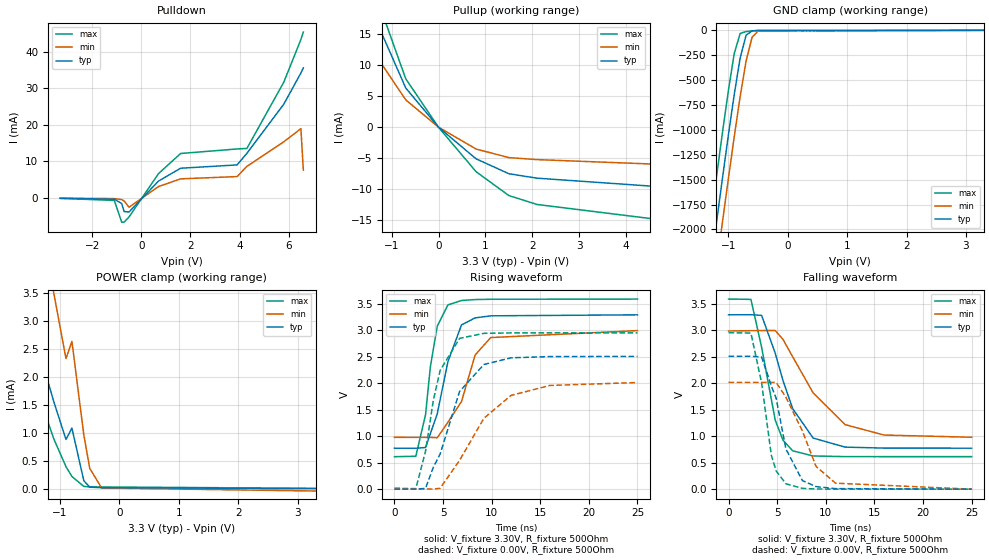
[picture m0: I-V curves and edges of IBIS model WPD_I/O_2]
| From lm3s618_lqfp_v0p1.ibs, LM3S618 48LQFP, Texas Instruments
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[Model]   WPD_I/O_2
Model_type   I/O
Vinl = 1.26
Vinh = 2.04
Vmeas = 1.65
| variable   typ   min   max
C_comp   9.739pF   9.739pF   9.739pF
[Model Spec]
Vinh+   1.91   1.78   2.04
Vinh-   1.90   1.76   2.03
Vinl+   1.40   1.27   1.54
Vinl-   1.39   1.26   1.53
| variable   typ   min   max
[Temperature Range]  25   85   -40
[Voltage Range]   3.3V   3.0V   3.6V
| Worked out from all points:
|   slope of the pulldown table from 0 to 0.495 V, typ, clamps not added: 143 ohm
|   slope of the pullup table from 0 to 0.495 V, typ, clamps not added: 143 ohm
|   GND clamp passes 1 mA (typ) near -0.48 V on its own axis
|   POWER clamp passes 1 mA (typ) near -0.79 V on its own axis
|   falling waveform, V_fixture 3.30V, R_fixture 500Ohm: 20-80 % time 2.98ns typ, 4.47ns min, 2.01ns max; typ from 3.29 V to 0.774 V
|   rising waveform, V_fixture 3.30V, R_fixture 500Ohm: 20-80 % time 1.93ns typ, 2.61ns min, 1.4ns max; typ from 0.774 V to 3.3 V
|   falling waveform, V_fixture 0.00V, R_fixture 500Ohm: 20-80 % time 2.07ns typ, 2.83ns min, 1.51ns max; typ from 2.51 V to 0 V
|   rising waveform, V_fixture 0.00V, R_fixture 500Ohm: 20-80 % time 2.98ns typ, 4.63ns min, 1.94ns max; typ from 0.003 V to 2.51 V
[Pulldown]
|  Voltage   I(typ)   I(min)   I(max)
-3.3V     -64.09uA   -36.39uA   -91.03uA
-1.1V     -317.9uA   -146.8uA   -640.8uA
-800mV    -1.497mA   -417.3uA   -6.593mA
-700mV    -3.676mA   -803.4uA   -6.572mA
-500mV    -3.809mA   -2.499mA   -5.157mA
700mV     4.647mA    3.147mA    6.675mA
1.6V      8.15mA     5.248mA    12.18mA
3.9V      9.062mA    5.872mA    13.42mA
4.3V      12.22mA    8.655mA    13.56mA
5.8V      25.62mA    15.36mA    31.63mA
6.5V      34.18mA    18.97mA    43.32mA
6.6V      35.58mA    7.622mA    45.36mA
[Pullup]
|  Voltage   I(typ)   I(min)   I(max)
-3.3V     48.77mA    30.88mA    64.31mA
-2V       27.6mA     18.17mA    34.71mA
-1.4V     18.3mA     12.15mA    22.84mA
-1.2V     14.98mA    10.08mA    18.46mA
-700mV    6.344mA    4.415mA    7.831mA
0V        -16.11uA   -8.757uA   -29.78uA
800mV     -5.128mA   -3.547mA   -7.217mA
1.5V      -7.548mA   -4.932mA   -11.08mA
2.1V      -8.262mA   -5.257mA   -12.52mA
5V        -9.795mA   -6.104mA   -15.25mA
5.8V      -11.66mA   -7.125mA   -18.25mA
6.6V      -15.14mA   -9.034mA   -24.12mA
[GND Clamp]
|  Voltage   I(typ)   I(min)   I(max)
-3.3V     -11.72A    -12.12A    -11.3A
-1.4V     -2.845A    -3.285A    -2.387A
-1.3V     -2.39A     -2.831A    -1.93A
-1.2V     -1.938A    -2.38A     -1.478A
-1.1V     -1.494A    -1.934A    -1.036A
-1V       -1.059A    -1.496A    -610.6mA
-900mV    -645mA     -1.069A    -232.9mA
-800mV    -277.1mA   -664.4mA   -31.59mA
-700mV    -48.56mA   -306.6mA   -12.1mA
-600mV    -5.561mA   -70.2mA    -6.281mA
-500mV    -1.172mA   -7.88mA    -2.176mA
3.3V      16.11uA    11.84uA    29.77uA
[POWER Clamp]
|  Voltage   I(typ)   I(min)   I(max)
-3.3V     12.42mA    17.27mA    12.25mA
-1.9V     4.935mA    8.337mA    4.102mA
-1.8V     4.461mA    7.714mA    3.616mA
-1.6V     3.549mA    6.478mA    2.703mA
-1.2V     1.906mA    4.063mA    1.182mA
-1.1V     1.542mA    3.476mA    880.4uA
-900mV    882uA      2.332mA    394.1uA
-800mV    1.086mA    2.641mA    218.2uA
-600mV    142.8uA    965.1uA    40.85uA
-500mV    27.22uA    363.6uA    30.71uA
-300mV    16.12uA    11.84uA    29.79uA
3.3V      -104.7pA   -42.65uA   5.692uA
[Ramp]
| variable   typ   min   max
dV/dt_f   1.51/2.98n   1.20/4.47n   1.79/2.01n
dV/dt_r   1.50/2.98n   1.20/4.63n   1.77/1.94n
R_load = 500Ohm
[Falling Waveform]
V_fixture = 3.30V
V_fixture_min = 3.00V
V_fixture_max = 3.60V
R_fixture = 500Ohm
|   Time   V(typ)   V(min)   V(max)
0s        3.294V     2.988V     3.591V
2.3ns     3.295V     2.994V     3.585V
3.4ns     3.283V     2.996V     2.681V
4.8ns     2.569V     2.997V     1.306V
5.6ns     2.051V     2.829V     925.4mV
6.6ns     1.52V      2.499V     724.4mV
8.7ns     965mV      1.82V      627.3mV
12ns      794.2mV    1.218V     614.8mV
16ns      775.8mV    1.022V     614.2mV
25ns      774.3mV    980.9mV    614.1mV
[Rising Waveform]
V_fixture = 3.30V
V_fixture_min = 3.00V
V_fixture_max = 3.60V
R_fixture = 500Ohm
|   Time   V(typ)   V(min)   V(max)
0s        774.3mV    980.1mV    614.1mV
2.2ns     774.3mV    980mV      622.5mV
3.2ns     787mV      979.9mV    1.407V
3.7ns     1.052V     980.1mV    2.318V
4.4ns     1.421V     971mV      3.079V
5.5ns     2.409V     1.264V     3.484V
6.9ns     3.106V     1.658V     3.567V
8.3ns     3.238V     2.536V     3.585V
9.9ns     3.277V     2.866V     3.59V
25ns      3.296V     2.998V     3.594V
[Falling Waveform]
V_fixture = 0.00V
V_fixture_min = 0.00V
V_fixture_max = 0.00V
R_fixture = 500Ohm
|   Time   V(typ)   V(min)   V(max)
0s        2.51V      2.018V     2.956V
2.3ns     2.51V      2.018V     2.949V
3.4ns     2.496V     2.018V     2.006V
4.4ns     1.953V     2.018V     640.4mV
4.9ns     1.714V     2.015V     343.1mV
5.9ns     759.2mV    1.738V     101.1mV
7.6ns     161.2mV    1.097V     14.72mV
9ns       48.57mV    430.3mV    3.464mV
11ns      10.29mV    113.3mV    565.4uV
25ns      33.59uV    149.8uV    22.64uV
[Rising Waveform]
V_fixture = 0.00V
V_fixture_min = 0.00V
V_fixture_max = 0.00V
R_fixture = 500Ohm
|   Time   V(typ)   V(min)   V(max)
0s        2.843mV    22.04mV    193.5uV
2.2ns     619.5uV    6.782mV    10.99mV
3.2ns     15.34mV    4.117mV    717mV
4ns       413.4mV    1.735mV    1.68V
4.7ns     664.9mV    17.25mV    2.244V
6.7ns     1.847V     544.4mV    2.851V
9.2ns     2.357V     1.34V      2.946V
12ns      2.483V     1.773V     2.954V
16ns      2.507V     1.961V     2.955V
25ns      2.51V      2.016V     2.955V
